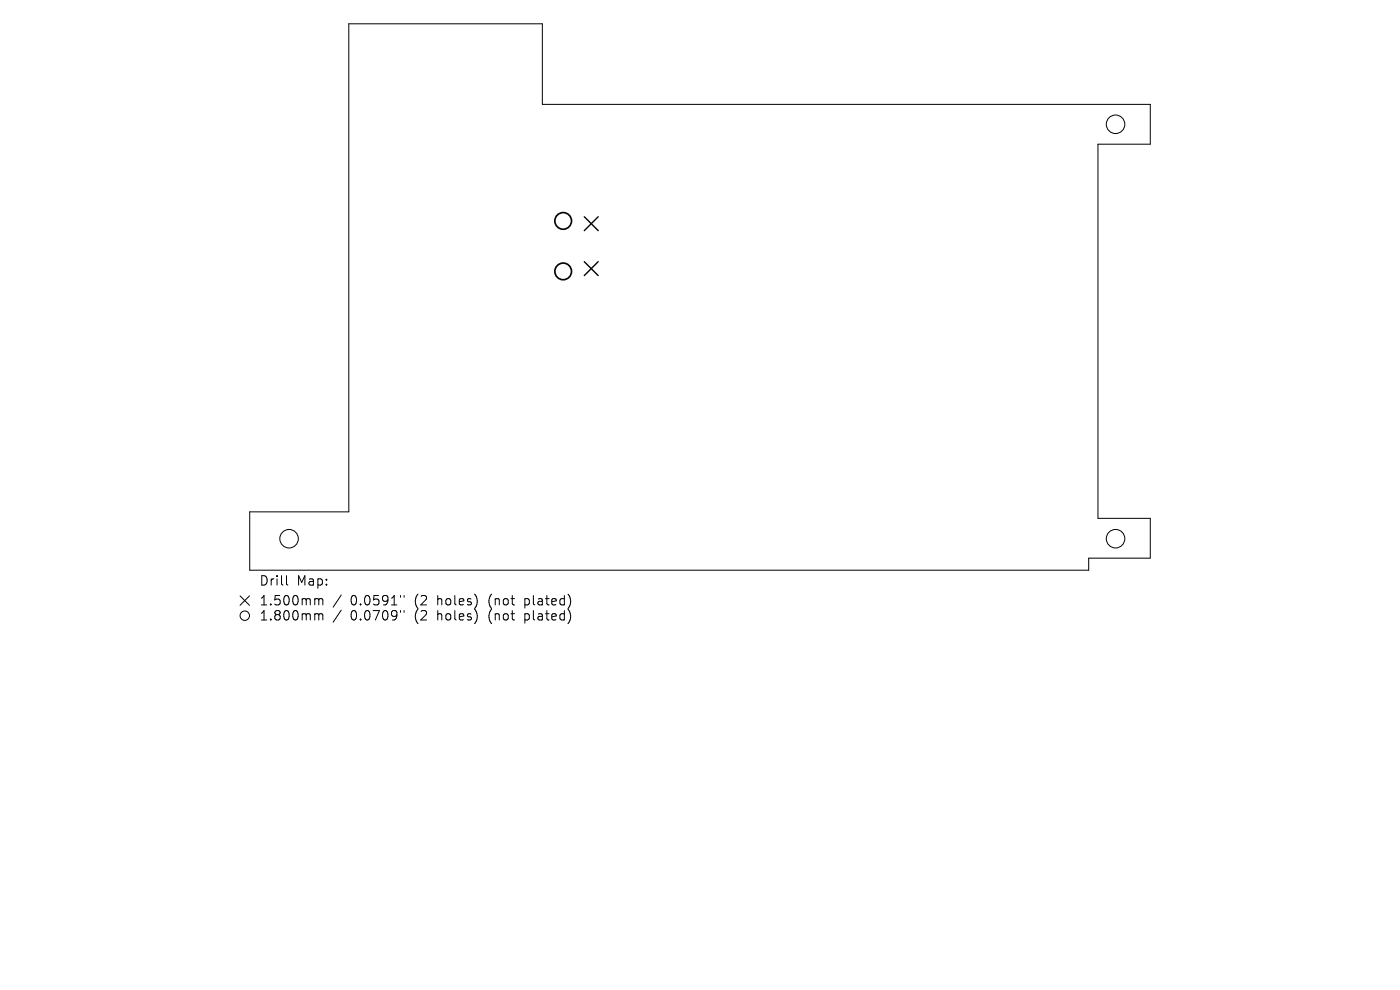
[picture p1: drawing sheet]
<svg xmlns="http://www.w3.org/2000/svg" width="297mm" height="210mm" viewBox="0 0 297 210" stroke-linecap="round" stroke-linejoin="round" font-family="sans-serif">
<defs><g id="words">
<g font-size="2.8">
<text x="54.9" y="124.5">Drill</text>
<text x="62.9" y="124.5">Map:</text>
<text x="54.9" y="128.7">1.500mm</text>
<text x="54.9" y="131.9">1.800mm</text>
<text x="74.4" y="128.7">0.0591&quot;</text>
<text x="74.4" y="131.9">0.0709&quot;</text>
<text x="88.1" y="128.7">(2</text>
<text x="88.1" y="131.9">(2</text>
<text x="93.1" y="128.7">holes)</text>
<text x="93.1" y="131.9">holes)</text>
<text x="104.1" y="128.7">(not</text>
<text x="104.1" y="131.9">(not</text>
<text x="111.9" y="128.7">plated)</text>
<text x="111.9" y="131.9">plated)</text>
</g>
</g></defs>
<g fill="none" stroke="#000" stroke-width=".21">
<path d="M74 5h41.1v17.1h128.9v8.5h-11.1v79.4h11.1v8.4h-13v2.6h-178v-12.4h21zM50.9 126.4l2 2M52.9 126.4l-2 2M60.8 122.1v1.7l.3 .3M67.1 127l.4 .1 .1 .2M67.1 130.2h.2l.3 .3M67.6 127.3l.3-.3 .5 .1 .1 1.2M67.6 127.3v1M67.6 130.5v1M67.6 130.5l.3-.3 .5 .1 .1 1.2M72.4 126.2l-1.7 2.6M72.4 129.4l-1.7 2.6"/>
<path d="M85 126.3v.4M85 129.5v.4M85.7 126.3v.4M85.7 129.5v.4"/>
<circle cx="236.7" cy="26.4" r="1.96"/>
<circle cx="61.3" cy="114.3" r="1.96"/>
<circle cx="236.7" cy="114.3" r="1.96"/>
<circle cx="51.9" cy="130.6" r="1"/>
</g>
<path d="M124 46l2.9 2.9M124 55.5l2.9 3M126.9 46l-2.9 2.9M126.9 55.5l-2.9 3" fill="none" stroke="#000" stroke-width=".29"/>
<g fill="none" stroke="#000" stroke-width=".35">
<circle cx="119.5" cy="46.9" r="1.77"/>
<circle cx="119.5" cy="57.6" r="1.77"/>
</g>
<use href="#words"/>
</svg>
